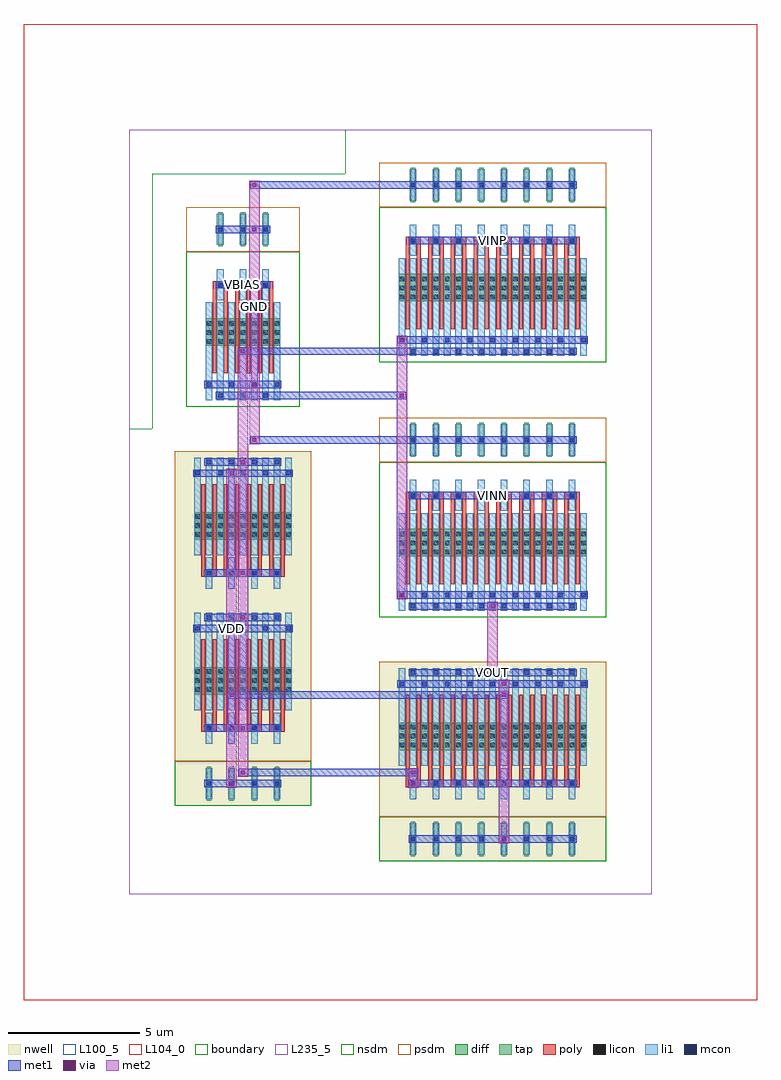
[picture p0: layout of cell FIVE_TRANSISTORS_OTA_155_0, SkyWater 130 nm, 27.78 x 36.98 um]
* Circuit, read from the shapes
.subckt FIVE_TRANSISTORS_OTA_155_0 GND VBIAS VDD VINN VINP VOUT
XM1 n1 VBIAS GND GND sky130_fd_pr__nfet_01v8 w=1.05 l=0.15 m=6
XM2 VOUT VINN n1 GND sky130_fd_pr__nfet_01v8 w=1.05 l=0.15 m=16
XM3 n2 VINP n1 GND sky130_fd_pr__nfet_01v8 w=1.05 l=0.15 m=16
XM4 n2 n2 VDD VDD sky130_fd_pr__pfet_01v8 w=1.05 l=0.15 m=16
XM5 VOUT n2 VDD VDD sky130_fd_pr__pfet_01v8 w=1.05 l=0.15 m=16
.ends

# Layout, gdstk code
from math import pi, radians
import gdstk
lib = gdstk.Library(unit=1e-6, precision=1e-09)
def R(c, l, rs):  # rectangles x0, y0, x1, y1
    for r in rs: c.add(gdstk.rectangle(r[:2], r[2:], *l))
def A(c, l, x, y, w, h, nx, ny, dx, dy):  # array of equal rectangles
    R(c, l, [(x+i*dx, y+j*dy, x+i*dx+w, y+j*dy+h) for i in range(nx) for j in range(ny)])
def P(c, l, *ps):  # polygons
    for p in ps: c.add(gdstk.Polygon(p, *l))
nwell = (64, 20)
diff = (65, 20)
tap = (65, 44)
poly = (66, 20)
licon = (66, 44)
li1 = (67, 20)
mcon = (67, 44)
met1 = (68, 20)
via = (68, 44)
met2 = (69, 20)
nsdm = (93, 44)
psdm = (94, 20)
L100_5 = (100, 5)
L104_0 = (104, 0)
boundary = (235, 4)
L235_5 = (235, 5)

dcl_pmos_s_58200762_x4_y = lib.new_cell('DCL_PMOS_S_58200762_X4_Y2_1746735325')
R(dcl_pmos_s_58200762_x4_y, nwell, [(1.29,0.84,6.45,14.28)])
R(dcl_pmos_s_58200762_x4_y, diff, [(2.025,3.15,5.715,4.2), (2.025,9.03,5.715,10.08)])
A(dcl_pmos_s_58200762_x4_y, tap, 2.495, 12.795, 0.17, 1.29, 4, 1, 0.86, 0)
A(dcl_pmos_s_58200762_x4_y, poly, 2.29, 2.1, 0.15, 3.36, 8, 2, 0.43, 5.88)
A(dcl_pmos_s_58200762_x4_y, poly, 2.29, 5.325, 0.58, 0.27, 4, 2, 0.86, 5.88)
A(dcl_pmos_s_58200762_x4_y, licon, 2.065, 3.23, 0.17, 0.17, 3, 3, 0.43, 0.34)
A(dcl_pmos_s_58200762_x4_y, licon, 2.925, 3.23, 0.17, 0.17, 3, 3, 0.43, 0.34)
A(dcl_pmos_s_58200762_x4_y, licon, 3.785, 3.23, 0.17, 0.17, 3, 3, 0.43, 0.34)
A(dcl_pmos_s_58200762_x4_y, licon, 4.645, 3.23, 0.17, 0.17, 3, 3, 0.43, 0.34)
A(dcl_pmos_s_58200762_x4_y, licon, 2.495, 5.375, 0.17, 0.17, 4, 2, 0.86, 5.88)
A(dcl_pmos_s_58200762_x4_y, licon, 2.065, 9.11, 0.17, 0.17, 3, 3, 0.43, 0.34)
A(dcl_pmos_s_58200762_x4_y, licon, 2.925, 9.11, 0.17, 0.17, 3, 3, 0.43, 0.34)
A(dcl_pmos_s_58200762_x4_y, licon, 3.785, 9.11, 0.17, 0.17, 3, 3, 0.43, 0.34)
A(dcl_pmos_s_58200762_x4_y, licon, 4.645, 9.11, 0.17, 0.17, 3, 3, 0.43, 0.34)
R(dcl_pmos_s_58200762_x4_y, licon, [(2.495,13.355,2.665,13.525), (2.495,13.355,2.665,13.525), (3.355,13.355,3.525,13.525), (3.355,13.355,3.525,13.525), (4.215,13.355,4.385,13.525), (4.215,13.355,4.385,13.525), (5.075,13.355,5.245,13.525), (5.075,13.355,5.245,13.525)])
A(dcl_pmos_s_58200762_x4_y, li1, 2.025, 1.09, 0.25, 3.7, 9, 2, 0.43, 5.88)
A(dcl_pmos_s_58200762_x4_y, li1, 2.455, 4.87, 0.25, 1.18, 4, 2, 0.86, 5.88)
A(dcl_pmos_s_58200762_x4_y, li1, 2.455, 12.85, 0.25, 1.18, 4, 1, 0.86, 0)
A(dcl_pmos_s_58200762_x4_y, mcon, 2.495, 1.175, 0.17, 0.17, 4, 2, 0.86, 4.2)
A(dcl_pmos_s_58200762_x4_y, mcon, 2.065, 1.595, 0.17, 0.17, 5, 2, 0.86, 5.88)
A(dcl_pmos_s_58200762_x4_y, mcon, 2.495, 7.055, 0.17, 0.17, 4, 2, 0.86, 4.2)
A(dcl_pmos_s_58200762_x4_y, mcon, 2.495, 13.355, 0.17, 0.17, 4, 1, 0.86, 0)
R(dcl_pmos_s_58200762_x4_y, met1, [(2.41,1.12,5.33,1.4), (1.98,1.54,5.76,1.82), (2.41,5.32,5.33,5.6), (2.41,7,5.33,7.28), (1.98,7.42,5.76,7.7), (2.41,11.2,5.33,11.48), (2.41,13.3,5.33,13.58)])
A(dcl_pmos_s_58200762_x4_y, via, 4.225, 1.605, 0.15, 0.15, 1, 3, 0, 5.88)
R(dcl_pmos_s_58200762_x4_y, via, [(3.795,1.185,3.945,1.335), (3.795,5.385,3.945,5.535), (3.795,7.065,3.945,7.215), (3.795,11.265,3.945,11.415)])
R(dcl_pmos_s_58200762_x4_y, met2, [(3.67,1.1,4.07,11.5), (4.1,1.52,4.5,13.6)])
R(dcl_pmos_s_58200762_x4_y, nsdm, [(1.29,12.6,6.45,14.28)])
R(dcl_pmos_s_58200762_x4_y, psdm, [(1.29,0.84,6.45,12.6)])
R(dcl_pmos_s_58200762_x4_y, L100_5, [(0,0,8.17,17.64)])
R(dcl_pmos_s_58200762_x4_y, boundary, [(0,0,8.17,17.64)])

nmos_s_45989876_x3_y1_17 = lib.new_cell('NMOS_S_45989876_X3_Y1_1746735328')
R(nmos_s_45989876_x3_y1_17, diff, [(2.025,3.15,4.855,4.2)])
A(nmos_s_45989876_x3_y1_17, tap, 2.495, 6.915, 0.17, 1.29, 3, 1, 0.86, 0)
A(nmos_s_45989876_x3_y1_17, poly, 2.29, 2.1, 0.15, 3.36, 6, 1, 0.43, 0)
A(nmos_s_45989876_x3_y1_17, poly, 2.29, 5.325, 0.58, 0.27, 3, 1, 0.86, 0)
A(nmos_s_45989876_x3_y1_17, licon, 2.065, 3.23, 0.17, 0.17, 3, 3, 0.43, 0.34)
A(nmos_s_45989876_x3_y1_17, licon, 2.925, 3.23, 0.17, 0.17, 3, 3, 0.43, 0.34)
A(nmos_s_45989876_x3_y1_17, licon, 3.785, 3.23, 0.17, 0.17, 3, 3, 0.43, 0.34)
A(nmos_s_45989876_x3_y1_17, licon, 2.495, 5.375, 0.17, 0.17, 3, 2, 0.86, 2.1)
A(nmos_s_45989876_x3_y1_17, li1, 2.025, 1.09, 0.25, 3.7, 7, 1, 0.43, 0)
A(nmos_s_45989876_x3_y1_17, li1, 2.455, 4.87, 0.25, 1.18, 3, 2, 0.86, 2.1)
A(nmos_s_45989876_x3_y1_17, mcon, 2.495, 1.175, 0.17, 0.17, 3, 2, 0.86, 4.2)
A(nmos_s_45989876_x3_y1_17, mcon, 2.065, 1.595, 0.17, 0.17, 4, 1, 0.86, 0)
A(nmos_s_45989876_x3_y1_17, mcon, 2.495, 7.475, 0.17, 0.17, 3, 1, 0.86, 0)
R(nmos_s_45989876_x3_y1_17, met1, [(2.41,1.12,4.47,1.4), (1.98,1.54,4.9,1.82), (2.41,5.32,4.47,5.6), (2.41,7.42,4.47,7.7)])
R(nmos_s_45989876_x3_y1_17, via, [(3.795,1.605,3.945,1.755), (3.795,7.485,3.945,7.635)])
R(nmos_s_45989876_x3_y1_17, met2, [(3.67,1.52,4.07,7.72)])
R(nmos_s_45989876_x3_y1_17, nsdm, [(1.29,0.84,5.59,6.72)])
R(nmos_s_45989876_x3_y1_17, psdm, [(1.29,6.72,5.59,8.4)])
R(nmos_s_45989876_x3_y1_17, L100_5, [(0,0,7.31,9.66)])
R(nmos_s_45989876_x3_y1_17, boundary, [(0,0,7.31,9.66)])

pmos_s_87598739_x8_y1_17 = lib.new_cell('PMOS_S_87598739_X8_Y1_1746735329')
R(pmos_s_87598739_x8_y1_17, nwell, [(1.29,0.84,9.89,8.4)])
R(pmos_s_87598739_x8_y1_17, diff, [(2.025,3.15,9.155,4.2)])
A(pmos_s_87598739_x8_y1_17, tap, 2.495, 6.915, 0.17, 1.29, 8, 1, 0.86, 0)
A(pmos_s_87598739_x8_y1_17, poly, 2.29, 2.1, 0.15, 3.36, 16, 1, 0.43, 0)
A(pmos_s_87598739_x8_y1_17, poly, 2.29, 5.325, 0.58, 0.27, 8, 1, 0.86, 0)
A(pmos_s_87598739_x8_y1_17, licon, 2.065, 3.23, 0.17, 0.17, 3, 3, 0.43, 0.34)
A(pmos_s_87598739_x8_y1_17, licon, 2.925, 3.23, 0.17, 0.17, 3, 3, 0.43, 0.34)
A(pmos_s_87598739_x8_y1_17, licon, 3.785, 3.23, 0.17, 0.17, 3, 3, 0.43, 0.34)
A(pmos_s_87598739_x8_y1_17, licon, 4.645, 3.23, 0.17, 0.17, 3, 3, 0.43, 0.34)
A(pmos_s_87598739_x8_y1_17, licon, 5.505, 3.23, 0.17, 0.17, 3, 3, 0.43, 0.34)
A(pmos_s_87598739_x8_y1_17, licon, 6.365, 3.23, 0.17, 0.17, 3, 3, 0.43, 0.34)
A(pmos_s_87598739_x8_y1_17, licon, 7.225, 3.23, 0.17, 0.17, 3, 3, 0.43, 0.34)
A(pmos_s_87598739_x8_y1_17, licon, 8.085, 3.23, 0.17, 0.17, 3, 3, 0.43, 0.34)
A(pmos_s_87598739_x8_y1_17, licon, 2.495, 5.375, 0.17, 0.17, 8, 2, 0.86, 2.1)
A(pmos_s_87598739_x8_y1_17, li1, 2.025, 1.09, 0.25, 3.7, 17, 1, 0.43, 0)
A(pmos_s_87598739_x8_y1_17, li1, 2.455, 4.87, 0.25, 1.18, 8, 2, 0.86, 2.1)
A(pmos_s_87598739_x8_y1_17, mcon, 2.495, 1.175, 0.17, 0.17, 8, 2, 0.86, 4.2)
A(pmos_s_87598739_x8_y1_17, mcon, 2.065, 1.595, 0.17, 0.17, 9, 1, 0.86, 0)
A(pmos_s_87598739_x8_y1_17, mcon, 2.495, 7.475, 0.17, 0.17, 8, 1, 0.86, 0)
R(pmos_s_87598739_x8_y1_17, met1, [(2.41,1.12,8.77,1.4), (1.98,1.54,9.2,1.82), (2.41,5.32,8.77,5.6), (2.41,7.42,8.77,7.7)])
R(pmos_s_87598739_x8_y1_17, via, [(5.945,1.605,6.095,1.755), (5.945,7.485,6.095,7.635)])
R(pmos_s_87598739_x8_y1_17, met2, [(5.82,1.52,6.22,7.72)])
R(pmos_s_87598739_x8_y1_17, nsdm, [(1.29,6.72,9.89,8.4)])
R(pmos_s_87598739_x8_y1_17, psdm, [(1.29,0.84,9.89,6.72)])
R(pmos_s_87598739_x8_y1_17, L100_5, [(0,0,11.61,9.66)])
R(pmos_s_87598739_x8_y1_17, boundary, [(0,0,11.61,9.66)])

nmos_4t_76032320_x8_y1_1 = lib.new_cell('NMOS_4T_76032320_X8_Y1_1746735326')
R(nmos_4t_76032320_x8_y1_1, diff, [(2.025,3.15,9.155,4.2)])
A(nmos_4t_76032320_x8_y1_1, tap, 2.495, 6.915, 0.17, 1.29, 8, 1, 0.86, 0)
A(nmos_4t_76032320_x8_y1_1, poly, 2.29, 2.1, 0.15, 3.36, 16, 1, 0.43, 0)
A(nmos_4t_76032320_x8_y1_1, poly, 2.29, 5.325, 0.58, 0.27, 8, 1, 0.86, 0)
A(nmos_4t_76032320_x8_y1_1, licon, 2.065, 3.23, 0.17, 0.17, 3, 3, 0.43, 0.34)
A(nmos_4t_76032320_x8_y1_1, licon, 2.925, 3.23, 0.17, 0.17, 3, 3, 0.43, 0.34)
A(nmos_4t_76032320_x8_y1_1, licon, 3.785, 3.23, 0.17, 0.17, 3, 3, 0.43, 0.34)
A(nmos_4t_76032320_x8_y1_1, licon, 4.645, 3.23, 0.17, 0.17, 3, 3, 0.43, 0.34)
A(nmos_4t_76032320_x8_y1_1, licon, 5.505, 3.23, 0.17, 0.17, 3, 3, 0.43, 0.34)
A(nmos_4t_76032320_x8_y1_1, licon, 6.365, 3.23, 0.17, 0.17, 3, 3, 0.43, 0.34)
A(nmos_4t_76032320_x8_y1_1, licon, 7.225, 3.23, 0.17, 0.17, 3, 3, 0.43, 0.34)
A(nmos_4t_76032320_x8_y1_1, licon, 8.085, 3.23, 0.17, 0.17, 3, 3, 0.43, 0.34)
A(nmos_4t_76032320_x8_y1_1, licon, 2.495, 5.375, 0.17, 0.17, 8, 2, 0.86, 2.1)
A(nmos_4t_76032320_x8_y1_1, li1, 2.025, 1.09, 0.25, 3.7, 17, 1, 0.43, 0)
A(nmos_4t_76032320_x8_y1_1, li1, 2.455, 4.87, 0.25, 1.18, 8, 2, 0.86, 2.1)
A(nmos_4t_76032320_x8_y1_1, mcon, 2.495, 1.175, 0.17, 0.17, 8, 2, 0.86, 4.2)
A(nmos_4t_76032320_x8_y1_1, mcon, 2.065, 1.595, 0.17, 0.17, 9, 1, 0.86, 0)
A(nmos_4t_76032320_x8_y1_1, mcon, 2.495, 7.475, 0.17, 0.17, 8, 1, 0.86, 0)
R(nmos_4t_76032320_x8_y1_1, met1, [(2.41,1.12,8.77,1.4), (1.98,1.54,9.2,1.82), (2.41,5.32,8.77,5.6), (2.41,7.42,8.77,7.7)])
R(nmos_4t_76032320_x8_y1_1, nsdm, [(1.29,0.84,9.89,6.72)])
R(nmos_4t_76032320_x8_y1_1, psdm, [(1.29,6.72,9.89,8.4)])
R(nmos_4t_76032320_x8_y1_1, L100_5, [(0,0,11.61,9.66)])
R(nmos_4t_76032320_x8_y1_1, boundary, [(0,0,11.61,9.66)])

nmos_4t_93849565_x8_y1_1 = lib.new_cell('NMOS_4T_93849565_X8_Y1_1746735327')
R(nmos_4t_93849565_x8_y1_1, diff, [(2.025,3.15,9.155,4.2)])
A(nmos_4t_93849565_x8_y1_1, tap, 2.495, 6.915, 0.17, 1.29, 8, 1, 0.86, 0)
A(nmos_4t_93849565_x8_y1_1, poly, 2.29, 2.1, 0.15, 3.36, 16, 1, 0.43, 0)
A(nmos_4t_93849565_x8_y1_1, poly, 2.29, 5.325, 0.58, 0.27, 8, 1, 0.86, 0)
A(nmos_4t_93849565_x8_y1_1, licon, 2.065, 3.23, 0.17, 0.17, 3, 3, 0.43, 0.34)
A(nmos_4t_93849565_x8_y1_1, licon, 2.925, 3.23, 0.17, 0.17, 3, 3, 0.43, 0.34)
A(nmos_4t_93849565_x8_y1_1, licon, 3.785, 3.23, 0.17, 0.17, 3, 3, 0.43, 0.34)
A(nmos_4t_93849565_x8_y1_1, licon, 4.645, 3.23, 0.17, 0.17, 3, 3, 0.43, 0.34)
A(nmos_4t_93849565_x8_y1_1, licon, 5.505, 3.23, 0.17, 0.17, 3, 3, 0.43, 0.34)
A(nmos_4t_93849565_x8_y1_1, licon, 6.365, 3.23, 0.17, 0.17, 3, 3, 0.43, 0.34)
A(nmos_4t_93849565_x8_y1_1, licon, 7.225, 3.23, 0.17, 0.17, 3, 3, 0.43, 0.34)
A(nmos_4t_93849565_x8_y1_1, licon, 8.085, 3.23, 0.17, 0.17, 3, 3, 0.43, 0.34)
A(nmos_4t_93849565_x8_y1_1, licon, 2.495, 5.375, 0.17, 0.17, 8, 2, 0.86, 2.1)
A(nmos_4t_93849565_x8_y1_1, li1, 2.025, 1.09, 0.25, 3.7, 17, 1, 0.43, 0)
A(nmos_4t_93849565_x8_y1_1, li1, 2.455, 4.87, 0.25, 1.18, 8, 2, 0.86, 2.1)
A(nmos_4t_93849565_x8_y1_1, mcon, 2.495, 1.175, 0.17, 0.17, 8, 2, 0.86, 4.2)
A(nmos_4t_93849565_x8_y1_1, mcon, 2.065, 1.595, 0.17, 0.17, 9, 1, 0.86, 0)
A(nmos_4t_93849565_x8_y1_1, mcon, 2.495, 7.475, 0.17, 0.17, 8, 1, 0.86, 0)
R(nmos_4t_93849565_x8_y1_1, met1, [(2.41,1.12,8.77,1.4), (1.98,1.54,9.2,1.82), (2.41,5.32,8.77,5.6), (2.41,7.42,8.77,7.7)])
R(nmos_4t_93849565_x8_y1_1, nsdm, [(1.29,0.84,9.89,6.72)])
R(nmos_4t_93849565_x8_y1_1, psdm, [(1.29,6.72,9.89,8.4)])
R(nmos_4t_93849565_x8_y1_1, L100_5, [(0,0,11.61,9.66)])
R(nmos_4t_93849565_x8_y1_1, boundary, [(0,0,11.61,9.66)])

five_transistors_ota_155 = lib.new_cell('FIVE_TRANSISTORS_OTA_155_0')
R(five_transistors_ota_155, met1, [(10.59,4.06,10.91,4.34), (10.59,4.06,10.91,4.34), (10.59,4.06,10.91,4.34), (10.59,4.06,10.91,4.34), (4.14,4.48,4.46,4.76), (4.14,4.48,4.46,4.76), (4.14,4.48,4.46,4.76), (4.14,4.48,4.46,4.76), (4.3,4.48,10.75,4.76), (10.59,4.48,10.91,4.76), (10.59,4.48,10.91,4.76), (10.59,4.48,10.91,4.76), (10.59,4.48,10.91,4.76), (3.71,7.42,4.03,7.7), (3.71,7.42,4.03,7.7), (3.87,7.42,14.19,7.7), (14.03,7.42,14.35,7.7), (14.03,7.42,14.35,7.7), (13.6,8.26,13.92,8.54), (13.6,8.26,13.92,8.54), (13.6,10.78,13.92,11.06), (13.6,10.78,13.92,11.06), (10.16,11.2,10.48,11.48), (10.16,11.2,10.48,11.48), (4.57,17.08,4.89,17.36), (4.57,17.08,4.89,17.36), (4.73,17.08,10.75,17.36), (5.16,18.76,10.32,19.04), (10.16,18.76,10.48,19.04), (10.16,18.76,10.48,19.04), (10.16,18.76,10.48,19.04), (10.16,18.76,10.48,19.04), (4.14,20.44,4.46,20.72), (4.14,20.44,4.46,20.72), (4.3,20.44,10.75,20.72), (10.16,20.86,10.48,21.14), (10.16,20.86,10.48,21.14), (10.16,20.86,10.48,21.14), (10.16,20.86,10.48,21.14), (4.57,26.74,4.89,27.02), (4.57,26.74,4.89,27.02), (4.57,26.74,4.89,27.02), (4.57,26.74,4.89,27.02), (4.73,26.74,10.75,27.02)])
P(five_transistors_ota_155, met1, [(0,0),(0,0),(0,0),(0,0)],
  [(0,0),(0,0),(0,0),(0,0)],
  [(0,0),(0,0),(0,0),(0,0)],
  [(0,0),(0,0),(0,0),(0,0)],
  [(0,0),(0,0),(0,0),(0,0)],
  [(0,0),(0,0),(0,0),(0,0)],
  [(0,0),(0,0),(0,0),(0,0)],
  [(0,0),(0,0),(0,0),(0,0)],
  [(0,0),(0,0),(0,0),(0,0)],
  [(0,0),(0,0),(0,0),(0,0)],
  [(0,0),(0,0),(0,0),(0,0)],
  [(0,0),(0,0),(0,0),(0,0)],
  [(0,0),(0,0),(0,0),(0,0)],
  [(0,0),(0,0),(0,0),(0,0)],
  [(0,0),(0,0),(0,0),(0,0)],
  [(0,0),(0,0),(0,0),(0,0)])
R(five_transistors_ota_155, via, [(10.675,4.125,10.825,4.275), (10.675,4.125,10.825,4.275), (10.675,4.125,10.825,4.275), (10.675,4.125,10.825,4.275), (4.225,4.545,4.375,4.695), (4.225,4.545,4.375,4.695), (4.225,4.545,4.375,4.695), (4.225,4.545,4.375,4.695), (10.675,4.545,10.825,4.695), (10.675,4.545,10.825,4.695), (10.675,4.545,10.825,4.695), (10.675,4.545,10.825,4.695), (3.795,7.485,3.945,7.635), (3.795,7.485,3.945,7.635), (14.115,7.485,14.265,7.635), (14.115,7.485,14.265,7.635), (13.685,8.325,13.835,8.475), (13.685,8.325,13.835,8.475), (13.685,10.845,13.835,10.995), (13.685,10.845,13.835,10.995), (10.245,11.265,10.395,11.415), (10.245,11.265,10.395,11.415), (4.655,17.145,4.805,17.295), (4.655,17.145,4.805,17.295), (10.245,18.825,10.395,18.975), (10.245,18.825,10.395,18.975), (10.245,18.825,10.395,18.975), (10.245,18.825,10.395,18.975), (4.225,20.505,4.375,20.655), (4.225,20.505,4.375,20.655), (10.245,20.925,10.395,21.075), (10.245,20.925,10.395,21.075), (10.245,20.925,10.395,21.075), (10.245,20.925,10.395,21.075), (4.655,26.805,4.805,26.955), (4.655,26.805,4.805,26.955), (4.655,26.805,4.805,26.955), (4.655,26.805,4.805,26.955)])
R(five_transistors_ota_155, met2, [(10.55,4.04,10.95,4.36), (10.55,4.04,10.95,4.36), (10.55,4.04,10.95,4.36), (10.55,4.04,10.95,4.36), (10.55,4.2,10.95,4.62), (4.1,4.46,4.5,4.78), (4.1,4.46,4.5,4.78), (4.1,4.46,4.5,4.78), (4.1,4.46,4.5,4.78), (10.55,4.46,10.95,4.78), (10.55,4.46,10.95,4.78), (10.55,4.46,10.95,4.78), (10.55,4.46,10.95,4.78), (4.1,4.62,4.5,6.3), (3.67,7.4,4.07,7.72), (3.67,7.4,4.07,7.72), (13.99,7.4,14.39,7.72), (13.99,7.4,14.39,7.72), (13.56,8.24,13.96,8.56), (13.56,8.24,13.96,8.56), (13.56,8.4,13.96,10.92), (13.56,10.76,13.96,11.08), (13.56,10.76,13.96,11.08), (10.12,11.18,10.52,11.5), (10.12,11.18,10.52,11.5), (10.12,11.34,10.52,18.9), (4.1,16.38,4.5,20.58), (4.53,17.06,4.93,17.38), (4.53,17.06,4.93,17.38), (4.53,17.22,4.93,19.32), (10.12,18.74,10.52,19.06), (10.12,18.74,10.52,19.06), (10.12,18.74,10.52,19.06), (10.12,18.74,10.52,19.06), (10.12,18.9,10.52,21), (4.1,20.42,4.5,20.74), (4.1,20.42,4.5,20.74), (10.12,20.84,10.52,21.16), (10.12,20.84,10.52,21.16), (10.12,20.84,10.52,21.16), (10.12,20.84,10.52,21.16), (4.53,25.2,4.93,26.88), (4.53,26.72,4.93,27.04), (4.53,26.72,4.93,27.04), (4.53,26.72,4.93,27.04), (4.53,26.72,4.93,27.04)])
P(five_transistors_ota_155, met2, [(0,0),(0,0),(0,0),(0,0)],
  [(0,0),(0,0),(0,0),(0,0)],
  [(0,0),(0,0),(0,0),(0,0)],
  [(0,0),(0,0),(0,0),(0,0)],
  [(0,0),(0,0),(0,0),(0,0)],
  [(0,0),(0,0),(0,0),(0,0)])
R(five_transistors_ota_155, L104_0, [(-4,-4,23.78,32.98)])
R(five_transistors_ota_155, L235_5, [(0,0,19.78,28.98)])
five_transistors_ota_155.add(gdstk.Reference(dcl_pmos_s_58200762_x4_y, (8.17,17.64), rotation=pi))
five_transistors_ota_155.add(gdstk.Reference(nmos_s_45989876_x3_y1_17, (0.86,17.64)))
five_transistors_ota_155.add(gdstk.Reference(pmos_s_87598739_x8_y1_17, (8.17,9.66), x_reflection=True))
five_transistors_ota_155.add(gdstk.Reference(nmos_4t_76032320_x8_y1_1, (8.17,9.66)))
five_transistors_ota_155.add(gdstk.Reference(nmos_4t_93849565_x8_y1_1, (8.17,19.32)))
five_transistors_ota_155.add(gdstk.Label('VDD', (3.87,10.08), layer=69, texttype=5))
five_transistors_ota_155.add(gdstk.Label('VBIAS', (4.3,23.1), layer=68, texttype=5))
five_transistors_ota_155.add(gdstk.Label('GND', (4.73,22.26), layer=69, texttype=5))
five_transistors_ota_155.add(gdstk.Label('VOUT', (13.76,8.4), layer=68, texttype=5))
five_transistors_ota_155.add(gdstk.Label('VINN', (13.76,15.12), layer=68, texttype=5))
five_transistors_ota_155.add(gdstk.Label('VINP', (13.76,24.78), layer=68, texttype=5))

lib.write_gds('FIVE_TRANSISTORS_OTA_155_0.gds')
